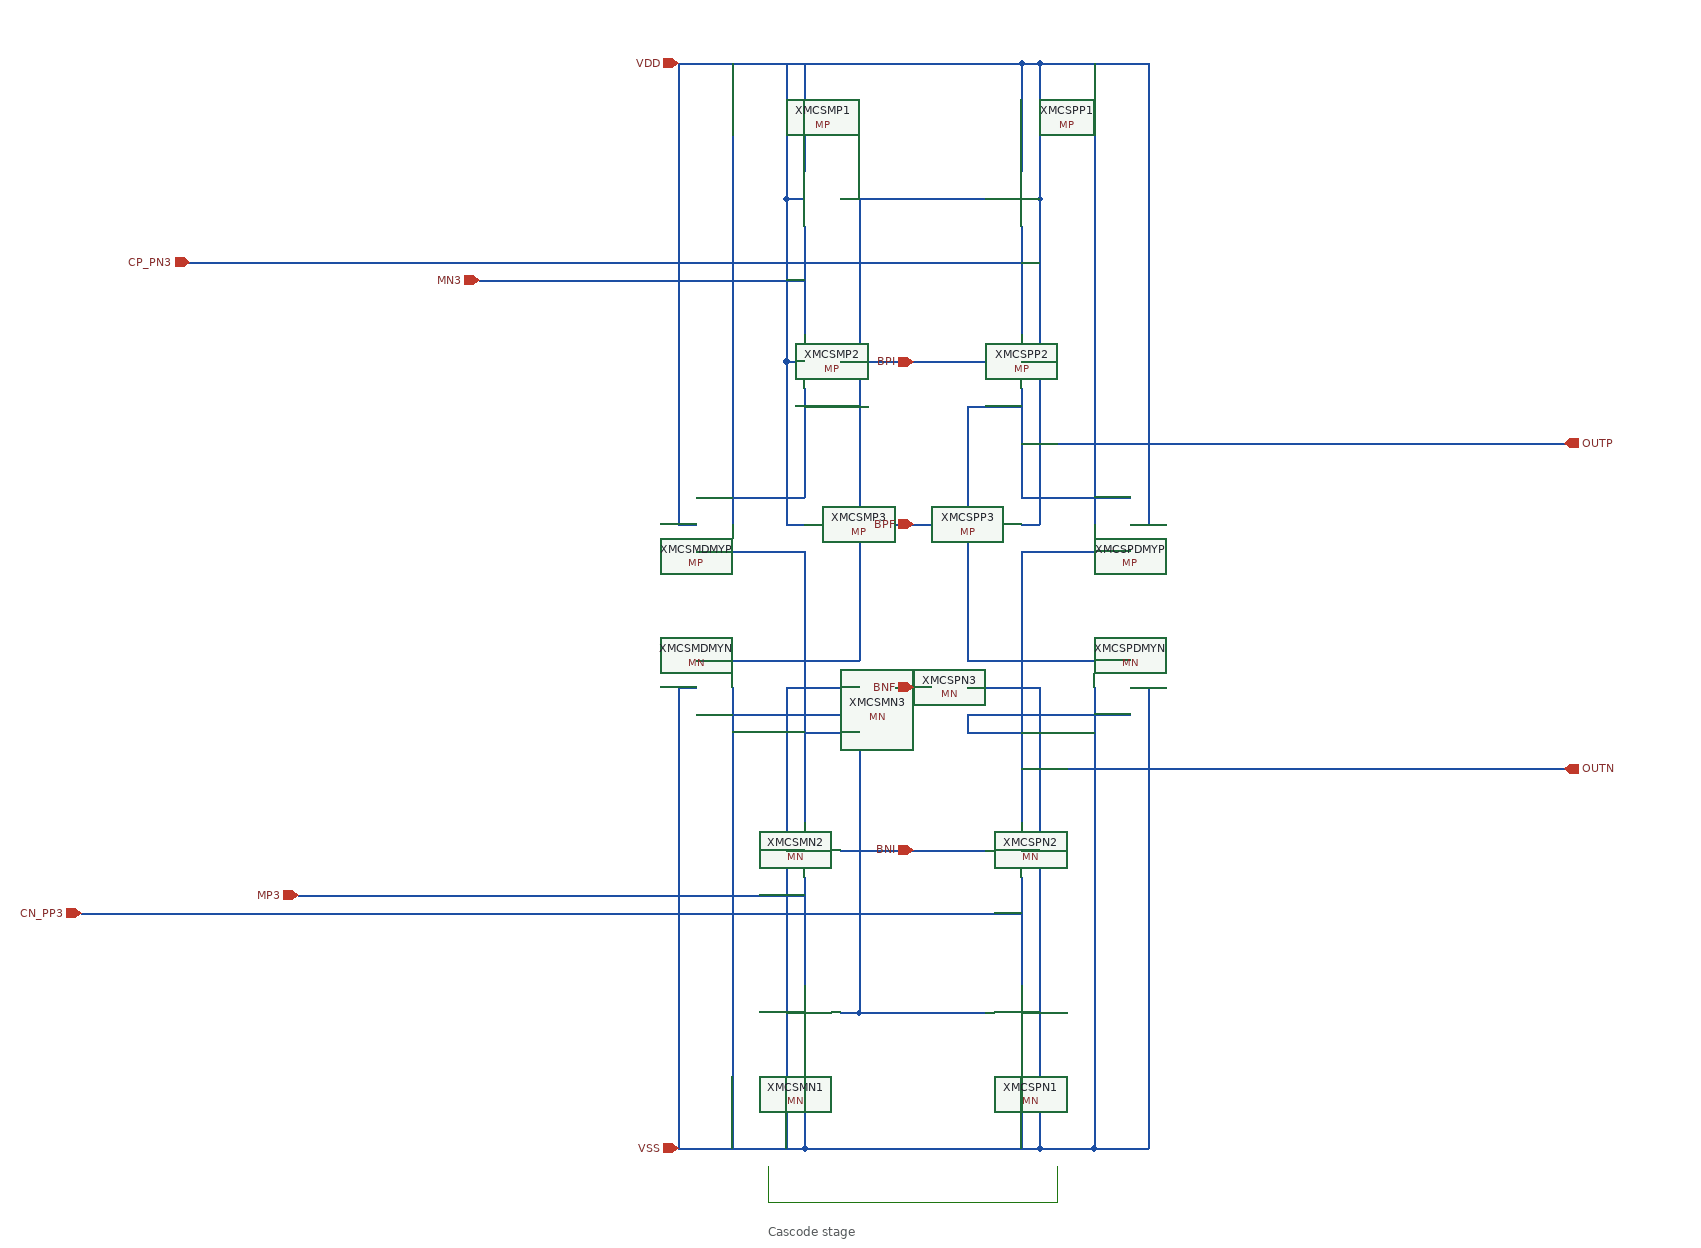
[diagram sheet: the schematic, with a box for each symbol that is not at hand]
v {xschem version=3.4.8RC file_version=1.3}
G {}
K {}
V {}
S {}
F {}
E {}
L 4 1640 20 1640 60 {}
L 4 1640 60 1880 60 {}
L 4 1960 20 1960 60 {}
L 4 1880 60 1960 60 {}
T {Cascode stage} 1640 80 0 0 0.4 0.4 {}
N 1680 -1020 1680 -900 {lab=MN3}
N 1660 -870 1680 -870 {lab=VDD}
N 1660 -1050 1660 -870 {lab=VDD}
N 1660 -1050 1680 -1050 {lab=VDD}
N 1660 -1050 1680 -1050 {lab=VDD}
N 1660 -1080 1660 -1050 {lab=VDD}
N 1680 -840 1680 -720 {lab=#net1}
N 1660 -690 1680 -690 {lab=VDD}
N 1660 -870 1660 -690 {lab=VDD}
N 1680 -1200 1680 -1080 {lab=VDD}
N 1660 -1200 1660 -1080 {lab=VDD}
N 1660 -1200 1680 -1200 {lab=VDD}
N 1720 -1050 1760 -1050 {lab=#net1}
N 1720 -870 1760 -870 {lab=BPF}
N 1720 -690 1880 -690 {lab=BPF}
N 1920 -1020 1920 -900 {lab=CP_PN3}
N 1920 -870 1940 -870 {lab=VDD}
N 1940 -1050 1940 -870 {lab=VDD}
N 1920 -1050 1940 -1050 {lab=VDD}
N 1920 -1050 1940 -1050 {lab=VDD}
N 1940 -1080 1940 -1050 {lab=VDD}
N 1920 -840 1920 -720 {lab=OUTP}
N 1920 -690 1940 -690 {lab=VDD}
N 1940 -870 1940 -690 {lab=VDD}
N 1920 -1200 1920 -1080 {lab=VDD}
N 1940 -1200 1940 -1080 {lab=VDD}
N 1920 -1200 1940 -1200 {lab=VDD}
N 1840 -1050 1880 -1050 {lab=#net1}
N 1840 -870 1880 -870 {lab=BPF}
N 1720 -690 1880 -690 {lab=BPF}
N 1560 -1200 1920 -1200 {lab=VDD}
N 1760 -1050 1840 -1050 {lab=#net1}
N 1760 -870 1840 -870 {lab=BPF}
N 1680 -300 1680 -180 {lab=MP3}
N 1660 -150 1680 -150 {lab=VSS}
N 1660 -330 1680 -330 {lab=VSS}
N 1680 -120 1680 0 {lab=VSS}
N 1660 -510 1660 0 {lab=VSS}
N 1720 -510 1740 -510 {lab=VSS}
N 1660 -510 1720 -510 {lab=VSS}
N 1740 -1050 1740 -540 {lab=#net1}
N 1680 -820 1740 -820 {lab=#net1}
N 1680 -460 1740 -460 {lab=#net2}
N 1740 -480 1740 -150 {lab=#net2}
N 1720 -150 1740 -150 {lab=#net2}
N 1920 -300 1920 -180 {lab=CN_PP3}
N 1920 -120 1920 0 {lab=VSS}
N 1940 -510 1940 0 {lab=VSS}
N 1920 -150 1940 -150 {lab=VSS}
N 1920 -330 1940 -330 {lab=VSS}
N 1860 -510 1940 -510 {lab=VSS}
N 1780 -510 1820 -510 {lab=BNF}
N 1860 -460 1920 -460 {lab=OUTN}
N 1740 -150 1880 -150 {lab=#net2}
N 1720 -330 1880 -330 {lab=BNI}
N 1120 -280 1680 -280 {lab=MP3}
N 880 -260 1920 -260 {lab=CN_PP3}
N 1680 0 1940 0 {lab=VSS}
N 1860 -480 1860 -460 {lab=OUTN}
N 1860 -820 1860 -540 {lab=OUTP}
N 1860 -820 1910 -820 {lab=OUTP}
N 1910 -820 1920 -820 {lab=OUTP}
N 1010 -980 1920 -980 {lab=CP_PN3}
N 1320 -960 1680 -960 {lab=MN3}
N 1000 -980 1010 -980 {lab=CP_PN3}
N 1600 -1200 1600 -690 {lab=VDD}
N 1540 -690 1560 -690 {lab=VDD}
N 1540 -1200 1540 -690 {lab=VDD}
N 1560 -660 1680 -660 {lab=#net2}
N 1920 -660 2040 -660 {lab=OUTN}
N 1920 -780 2520 -780 {lab=OUTP}
N 2040 -690 2060 -690 {lab=VDD}
N 2060 -1200 2060 -690 {lab=VDD}
N 2000 -1200 2000 -690 {lab=VDD}
N 1560 -540 1740 -540 {lab=#net1}
N 1920 -660 1920 -360 {lab=OUTN}
N 1680 -660 1680 -360 {lab=#net2}
N 1860 -540 2040 -540 {lab=OUTP}
N 2000 -510 2000 0 {lab=VSS}
N 1940 0 2000 0 {lab=VSS}
N 1920 -420 2520 -420 {lab=OUTN}
N 2040 -510 2060 -510 {lab=VSS}
N 2060 -510 2060 0 {lab=VSS}
N 1540 -510 1560 -510 {lab=VSS}
N 1540 -510 1540 -0 {lab=VSS}
N 1730 -480 1740 -480 {lab=#net2}
N 1600 -510 1600 -0 {lab=VSS}
N 1540 -1200 1560 -1200 {lab=VDD}
N 1540 -0 1680 -0 {lab=VSS}
N 2000 -0 2060 -0 {lab=VSS}
N 1940 -1200 2060 -1200 {lab=VDD}
N 1920 -720 2040 -720 {lab=OUTP}
N 1560 -720 1680 -720 {lab=#net1}
N 1560 -480 1730 -480 {lab=#net2}
N 1860 -480 2040 -480 {lab=OUTN}
C {IP62LIB/MP.sym} 1720 -1050 0 1 {name=XMCSMP1 model=PMOS w=13.2u l=5u m=16 as=19.8p ad=19.8p ps=16.2u pd=16.2u nrd=0 nrs=0}
C {IP62LIB/MP.sym} 1720 -870 0 1 {name=XMCSMP2 model=PMOS w=13.2u l=5u m=8 as=19.8p ad=19.8p ps=16.2u pd=16.2u nrd=0 nrs=0}
C {IP62LIB/MP.sym} 1720 -690 0 1 {name=XMCSMP3 model=PMOS w=13.2u l=5u m=4 as=19.8p ad=19.8p ps=16.2u pd=16.2u nrd=0 nrs=0}
C {IP62LIB/MP.sym} 1880 -1050 0 0 {name=XMCSPP1 model=PMOS w=13.2u l=5u m=16 as=19.8p ad=19.8p ps=16.2u pd=16.2u nrd=0 nrs=0}
C {IP62LIB/MP.sym} 1880 -870 0 0 {name=XMCSPP2 model=PMOS w=13.2u l=5u m=8 as=19.8p ad=19.8p ps=16.2u pd=16.2u nrd=0 nrs=0}
C {IP62LIB/MP.sym} 1880 -690 0 0 {name=XMCSPP3 model=PMOS w=13.2u l=5u m=4 as=19.8p ad=19.8p ps=16.2u pd=16.2u nrd=0 nrs=0}
C {IP62LIB/MN.sym} 1720 -330 0 1 {name=XMCSMN2 model=NMOS w=4.8u l=5u m=8 as=7.2p ad=7.2p ps=7.8u pd=7.8u nrd=0 nrs=0}
C {IP62LIB/MN.sym} 1720 -150 0 1 {name=XMCSMN1 model=NMOS w=4.8u l=5u m=16 as=7.2p ad=7.2p ps=7.8u pd=7.8u nrd=0 nrs=0}
C {IP62LIB/MN.sym} 1780 -510 0 1 {name=XMCSMN3 model=NMOS w=4.8u l=5u m=4 as=7.2p ad=7.2p ps=7.8u pd=7.8u nrd=0 nrs=0}
C {IP62LIB/MN.sym} 1820 -510 0 0 {name=XMCSPN3 model=NMOS w=4.8u l=5u m=4 as=7.2p ad=7.2p ps=7.8u pd=7.8u nrd=0 nrs=0}
C {IP62LIB/MN.sym} 1880 -330 0 0 {name=XMCSPN2 model=NMOS w=4.8u l=5u m=8 as=7.2p ad=7.2p ps=7.8u pd=7.8u nrd=0 nrs=0}
C {IP62LIB/MN.sym} 1880 -150 0 0 {name=XMCSPN1 model=NMOS w=4.8u l=5u m=16 as=7.2p ad=7.2p ps=7.8u pd=7.8u nrd=0 nrs=0}
C {devices/iopin.sym} 1540 -1200 2 0 {name=p22 lab=VDD}
C {devices/iopin.sym} 1540 0 2 0 {name=p23 lab=VSS}
C {devices/ipin.sym} 880 -260 0 0 {name=p7 lab=CN_PP3}
C {IP62LIB/MP.sym} 1600 -690 0 1 {name=XMCSMDMYP model=PMOS w=13.2u l=5u m=4 as=19.8p ad=19.8p ps=16.2u pd=16.2u nrd=0 nrs=0}
C {IP62LIB/MP.sym} 2000 -690 0 0 {name=XMCSPDMYP model=PMOS w=13.2u l=5u m=4 as=19.8p ad=19.8p ps=16.2u pd=16.2u nrd=0 nrs=0}
C {IP62LIB/MN.sym} 1600 -510 0 1 {name=XMCSMDMYN model=NMOS w=4.8u l=5u m=4 as=7.2p ad=7.2p ps=7.8u pd=7.8u nrd=0 nrs=0}
C {IP62LIB/MN.sym} 2000 -510 0 0 {name=XMCSPDMYN model=NMOS w=4.8u l=5u m=4 as=7.2p ad=7.2p ps=7.8u pd=7.8u nrd=0 nrs=0}
C {devices/ipin.sym} 1000 -980 0 0 {name=p31 lab=CP_PN3}
C {devices/ipin.sym} 1320 -960 0 0 {name=p32 lab=MN3}
C {devices/ipin.sym} 1120 -280 0 0 {name=p33 lab=MP3}
C {devices/opin.sym} 2520 -780 0 0 {name=p1 lab=OUTP}
C {devices/opin.sym} 2520 -420 0 0 {name=p2 lab=OUTN}
C {devices/ipin.sym} 1800 -330 1 0 {name=p3 lab=BNI}
C {devices/ipin.sym} 1800 -510 1 0 {name=p4 lab=BNF}
C {devices/ipin.sym} 1800 -690 1 0 {name=p5 lab=BPF}
C {devices/ipin.sym} 1800 -870 1 0 {name=p6 lab=BPI}
